VERSION 5.7 ;
  NOWIREEXTENSIONATPIN ON ;
  DIVIDERCHAR "/" ;
  BUSBITCHARS "[]" ;
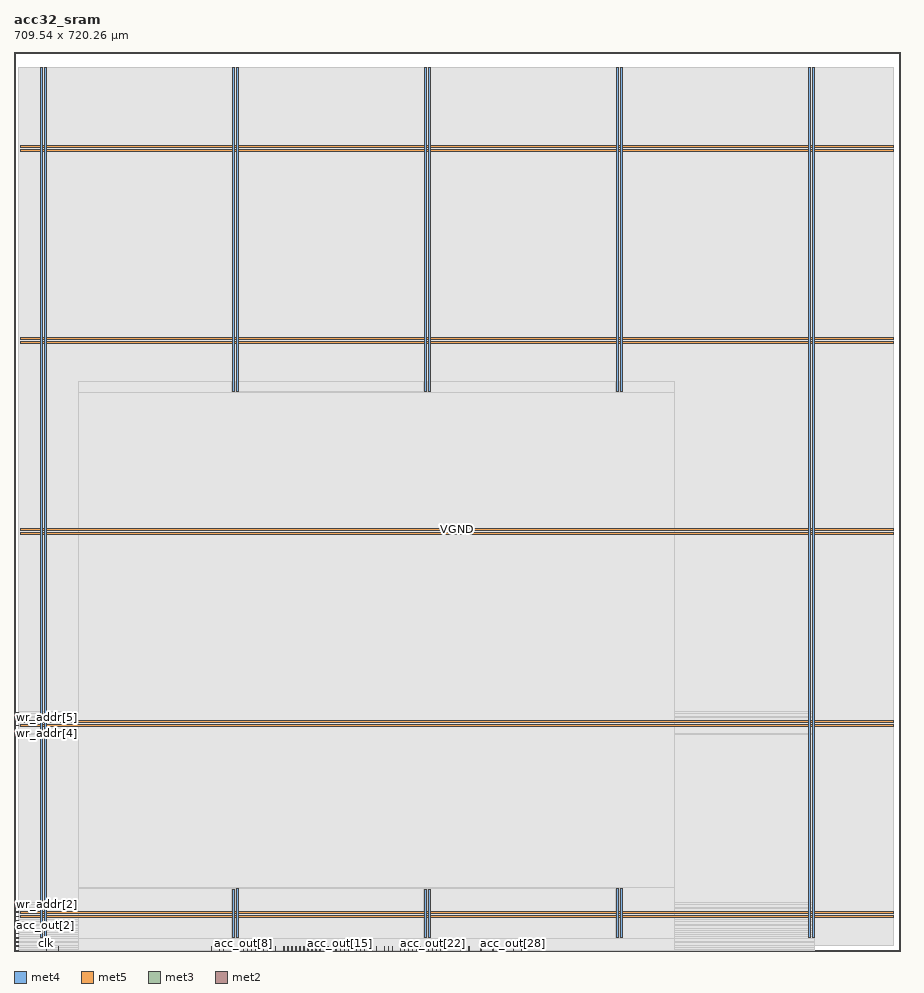
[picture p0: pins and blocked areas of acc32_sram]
MACRO acc32_sram
  CLASS BLOCK ;
  FOREIGN acc32_sram ;
  ORIGIN 0.000 0.000 ;
  SIZE 709.540 BY 720.260 ;
  PIN VGND
    DIRECTION INOUT ;
    USE GROUND ;
    PORT
      LAYER met4 ;
        RECT 24.340 10.640 25.940 707.440 ;
    END
    PORT
      LAYER met4 ;
        RECT 177.940 10.640 179.540 50.020 ;
    END
    PORT
      LAYER met4 ;
        RECT 177.940 447.480 179.540 707.440 ;
    END
    PORT
      LAYER met4 ;
        RECT 331.540 10.640 333.140 49.400 ;
    END
    PORT
      LAYER met4 ;
        RECT 331.540 447.480 333.140 707.440 ;
    END
    PORT
      LAYER met4 ;
        RECT 485.140 10.640 486.740 50.020 ;
    END
    PORT
      LAYER met4 ;
        RECT 485.140 447.480 486.740 707.440 ;
    END
    PORT
      LAYER met4 ;
        RECT 638.740 10.640 640.340 707.440 ;
    END
    PORT
      LAYER met5 ;
        RECT 5.280 30.030 704.040 31.630 ;
    END
    PORT
      LAYER met5 ;
        RECT 5.280 183.210 704.040 184.810 ;
    END
    PORT
      LAYER met5 ;
        RECT 5.280 336.390 704.040 337.990 ;
    END
    PORT
      LAYER met5 ;
        RECT 5.280 489.570 704.040 491.170 ;
    END
    PORT
      LAYER met5 ;
        RECT 5.280 642.750 704.040 644.350 ;
    END
  END VGND
  PIN VPWR
    DIRECTION INOUT ;
    USE POWER ;
    PORT
      LAYER met4 ;
        RECT 21.040 10.640 22.640 707.440 ;
    END
    PORT
      LAYER met4 ;
        RECT 174.640 10.640 176.240 49.400 ;
    END
    PORT
      LAYER met4 ;
        RECT 174.640 447.480 176.240 707.440 ;
    END
    PORT
      LAYER met4 ;
        RECT 328.240 10.640 329.840 49.400 ;
    END
    PORT
      LAYER met4 ;
        RECT 328.240 448.100 329.840 707.440 ;
    END
    PORT
      LAYER met4 ;
        RECT 481.840 10.640 483.440 50.020 ;
    END
    PORT
      LAYER met4 ;
        RECT 481.840 447.480 483.440 707.440 ;
    END
    PORT
      LAYER met4 ;
        RECT 635.440 10.640 637.040 707.440 ;
    END
    PORT
      LAYER met5 ;
        RECT 5.280 26.730 704.040 28.330 ;
    END
    PORT
      LAYER met5 ;
        RECT 5.280 179.910 704.040 181.510 ;
    END
    PORT
      LAYER met5 ;
        RECT 5.280 333.090 704.040 334.690 ;
    END
    PORT
      LAYER met5 ;
        RECT 5.280 486.270 704.040 487.870 ;
    END
    PORT
      LAYER met5 ;
        RECT 5.280 639.450 704.040 641.050 ;
    END
  END VPWR
  PIN acc_out[0]
    DIRECTION OUTPUT ;
    USE SIGNAL ;
    ANTENNADIFFAREA 0.445500 ;
    PORT
      LAYER met3 ;
        RECT 0.000 27.240 4.000 27.840 ;
    END
  END acc_out[0]
  PIN acc_out[10]
    DIRECTION OUTPUT ;
    USE SIGNAL ;
    ANTENNADIFFAREA 0.445500 ;
    PORT
      LAYER met2 ;
        RECT 206.170 0.000 206.450 4.000 ;
    END
  END acc_out[10]
  PIN acc_out[11]
    DIRECTION OUTPUT ;
    USE SIGNAL ;
    ANTENNADIFFAREA 0.445500 ;
    PORT
      LAYER met2 ;
        RECT 219.050 0.000 219.330 4.000 ;
    END
  END acc_out[11]
  PIN acc_out[12]
    DIRECTION OUTPUT ;
    USE SIGNAL ;
    ANTENNADIFFAREA 0.445500 ;
    PORT
      LAYER met2 ;
        RECT 225.490 0.000 225.770 4.000 ;
    END
  END acc_out[12]
  PIN acc_out[13]
    DIRECTION OUTPUT ;
    USE SIGNAL ;
    ANTENNADIFFAREA 0.445500 ;
    PORT
      LAYER met2 ;
        RECT 235.150 0.000 235.430 4.000 ;
    END
  END acc_out[13]
  PIN acc_out[14]
    DIRECTION OUTPUT ;
    USE SIGNAL ;
    ANTENNADIFFAREA 0.445500 ;
    PORT
      LAYER met2 ;
        RECT 241.590 0.000 241.870 4.000 ;
    END
  END acc_out[14]
  PIN acc_out[15]
    DIRECTION OUTPUT ;
    USE SIGNAL ;
    ANTENNADIFFAREA 0.445500 ;
    PORT
      LAYER met2 ;
        RECT 260.910 0.000 261.190 4.000 ;
    END
  END acc_out[15]
  PIN acc_out[16]
    DIRECTION OUTPUT ;
    USE SIGNAL ;
    ANTENNADIFFAREA 0.445500 ;
    PORT
      LAYER met2 ;
        RECT 270.570 0.000 270.850 4.000 ;
    END
  END acc_out[16]
  PIN acc_out[17]
    DIRECTION OUTPUT ;
    USE SIGNAL ;
    ANTENNADIFFAREA 0.445500 ;
    PORT
      LAYER met2 ;
        RECT 277.010 0.000 277.290 4.000 ;
    END
  END acc_out[17]
  PIN acc_out[18]
    DIRECTION OUTPUT ;
    USE SIGNAL ;
    ANTENNADIFFAREA 0.445500 ;
    PORT
      LAYER met2 ;
        RECT 283.450 0.000 283.730 4.000 ;
    END
  END acc_out[18]
  PIN acc_out[19]
    DIRECTION OUTPUT ;
    USE SIGNAL ;
    ANTENNADIFFAREA 0.445500 ;
    PORT
      LAYER met2 ;
        RECT 299.550 0.000 299.830 4.000 ;
    END
  END acc_out[19]
  PIN acc_out[1]
    DIRECTION OUTPUT ;
    USE SIGNAL ;
    ANTENNADIFFAREA 0.445500 ;
    PORT
      LAYER met3 ;
        RECT 0.000 17.040 4.000 17.640 ;
    END
  END acc_out[1]
  PIN acc_out[20]
    DIRECTION OUTPUT ;
    USE SIGNAL ;
    ANTENNADIFFAREA 0.445500 ;
    PORT
      LAYER met2 ;
        RECT 312.430 0.000 312.710 4.000 ;
    END
  END acc_out[20]
  PIN acc_out[21]
    DIRECTION OUTPUT ;
    USE SIGNAL ;
    ANTENNADIFFAREA 0.445500 ;
    PORT
      LAYER met2 ;
        RECT 322.090 0.000 322.370 4.000 ;
    END
  END acc_out[21]
  PIN acc_out[22]
    DIRECTION OUTPUT ;
    USE SIGNAL ;
    ANTENNADIFFAREA 0.445500 ;
    PORT
      LAYER met2 ;
        RECT 334.970 0.000 335.250 4.000 ;
    END
  END acc_out[22]
  PIN acc_out[23]
    DIRECTION OUTPUT ;
    USE SIGNAL ;
    ANTENNADIFFAREA 0.445500 ;
    PORT
      LAYER met2 ;
        RECT 341.410 0.000 341.690 4.000 ;
    END
  END acc_out[23]
  PIN acc_out[24]
    DIRECTION OUTPUT ;
    USE SIGNAL ;
    ANTENNADIFFAREA 0.445500 ;
    PORT
      LAYER met2 ;
        RECT 357.510 0.000 357.790 4.000 ;
    END
  END acc_out[24]
  PIN acc_out[25]
    DIRECTION OUTPUT ;
    USE SIGNAL ;
    ANTENNADIFFAREA 0.445500 ;
    PORT
      LAYER met2 ;
        RECT 363.950 0.000 364.230 4.000 ;
    END
  END acc_out[25]
  PIN acc_out[26]
    DIRECTION OUTPUT ;
    USE SIGNAL ;
    ANTENNADIFFAREA 0.445500 ;
    PORT
      LAYER met2 ;
        RECT 373.610 0.000 373.890 4.000 ;
    END
  END acc_out[26]
  PIN acc_out[27]
    DIRECTION OUTPUT ;
    USE SIGNAL ;
    ANTENNADIFFAREA 0.445500 ;
    PORT
      LAYER met2 ;
        RECT 383.270 0.000 383.550 4.000 ;
    END
  END acc_out[27]
  PIN acc_out[28]
    DIRECTION OUTPUT ;
    USE SIGNAL ;
    ANTENNADIFFAREA 0.445500 ;
    PORT
      LAYER met2 ;
        RECT 399.370 0.000 399.650 4.000 ;
    END
  END acc_out[28]
  PIN acc_out[29]
    DIRECTION OUTPUT ;
    USE SIGNAL ;
    ANTENNADIFFAREA 0.445500 ;
    PORT
      LAYER met2 ;
        RECT 405.810 0.000 406.090 4.000 ;
    END
  END acc_out[29]
  PIN acc_out[2]
    DIRECTION OUTPUT ;
    USE SIGNAL ;
    ANTENNADIFFAREA 0.445500 ;
    PORT
      LAYER met3 ;
        RECT 0.000 20.440 4.000 21.040 ;
    END
  END acc_out[2]
  PIN acc_out[30]
    DIRECTION OUTPUT ;
    USE SIGNAL ;
    ANTENNADIFFAREA 0.445500 ;
    PORT
      LAYER met2 ;
        RECT 409.030 0.000 409.310 4.000 ;
    END
  END acc_out[30]
  PIN acc_out[31]
    DIRECTION OUTPUT ;
    USE SIGNAL ;
    ANTENNADIFFAREA 0.445500 ;
    PORT
      LAYER met2 ;
        RECT 421.910 0.000 422.190 4.000 ;
    END
  END acc_out[31]
  PIN acc_out[3]
    DIRECTION OUTPUT ;
    USE SIGNAL ;
    ANTENNADIFFAREA 0.445500 ;
    PORT
      LAYER met3 ;
        RECT 0.000 10.240 4.000 10.840 ;
    END
  END acc_out[3]
  PIN acc_out[4]
    DIRECTION OUTPUT ;
    USE SIGNAL ;
    ANTENNADIFFAREA 0.445500 ;
    PORT
      LAYER met3 ;
        RECT 0.000 0.040 4.000 0.640 ;
    END
  END acc_out[4]
  PIN acc_out[5]
    DIRECTION OUTPUT ;
    USE SIGNAL ;
    ANTENNADIFFAREA 0.445500 ;
    PORT
      LAYER met3 ;
        RECT 0.000 13.640 4.000 14.240 ;
    END
  END acc_out[5]
  PIN acc_out[6]
    DIRECTION OUTPUT ;
    USE SIGNAL ;
    ANTENNADIFFAREA 0.445500 ;
    PORT
      LAYER met3 ;
        RECT 0.000 3.440 4.000 4.040 ;
    END
  END acc_out[6]
  PIN acc_out[7]
    DIRECTION OUTPUT ;
    USE SIGNAL ;
    ANTENNADIFFAREA 0.445500 ;
    PORT
      LAYER met3 ;
        RECT 0.000 6.840 4.000 7.440 ;
    END
  END acc_out[7]
  PIN acc_out[8]
    DIRECTION OUTPUT ;
    USE SIGNAL ;
    ANTENNADIFFAREA 0.445500 ;
    PORT
      LAYER met2 ;
        RECT 183.630 0.000 183.910 4.000 ;
    END
  END acc_out[8]
  PIN acc_out[9]
    DIRECTION OUTPUT ;
    USE SIGNAL ;
    ANTENNADIFFAREA 0.445500 ;
    PORT
      LAYER met2 ;
        RECT 193.290 0.000 193.570 4.000 ;
    END
  END acc_out[9]
  PIN clk
    DIRECTION INPUT ;
    USE SIGNAL ;
    ANTENNAGATEAREA 0.852000 ;
    PORT
      LAYER met2 ;
        RECT 25.850 0.000 26.130 4.000 ;
    END
  END clk
  PIN rst
    DIRECTION INPUT ;
    USE SIGNAL ;
    ANTENNAGATEAREA 0.196500 ;
    PORT
      LAYER met2 ;
        RECT 35.510 0.000 35.790 4.000 ;
    END
  END rst
  PIN wr_addr[0]
    DIRECTION INPUT ;
    USE SIGNAL ;
    ANTENNAGATEAREA 0.196500 ;
    PORT
      LAYER met3 ;
        RECT 0.000 34.040 4.000 34.640 ;
    END
  END wr_addr[0]
  PIN wr_addr[1]
    DIRECTION INPUT ;
    USE SIGNAL ;
    ANTENNAGATEAREA 0.196500 ;
    PORT
      LAYER met3 ;
        RECT 0.000 23.840 4.000 24.440 ;
    END
  END wr_addr[1]
  PIN wr_addr[2]
    DIRECTION INPUT ;
    USE SIGNAL ;
    ANTENNAGATEAREA 0.196500 ;
    PORT
      LAYER met3 ;
        RECT 0.000 30.640 4.000 31.240 ;
    END
  END wr_addr[2]
  PIN wr_addr[3]
    DIRECTION INPUT ;
    USE SIGNAL ;
    ANTENNAGATEAREA 0.196500 ;
    PORT
      LAYER met3 ;
        RECT 0.000 37.440 4.000 38.040 ;
    END
  END wr_addr[3]
  PIN wr_addr[4]
    DIRECTION INPUT ;
    USE SIGNAL ;
    ANTENNAGATEAREA 0.196500 ;
    PORT
      LAYER met3 ;
        RECT 0.000 173.440 4.000 174.040 ;
    END
  END wr_addr[4]
  PIN wr_addr[5]
    DIRECTION INPUT ;
    USE SIGNAL ;
    ANTENNAGATEAREA 0.196500 ;
    PORT
      LAYER met3 ;
        RECT 0.000 180.240 4.000 180.840 ;
    END
  END wr_addr[5]
  PIN wr_addr[6]
    DIRECTION INPUT ;
    USE SIGNAL ;
    ANTENNAGATEAREA 0.196500 ;
    PORT
      LAYER met3 ;
        RECT 0.000 183.640 4.000 184.240 ;
    END
  END wr_addr[6]
  PIN wr_addr[7]
    DIRECTION INPUT ;
    USE SIGNAL ;
    ANTENNAGATEAREA 0.196500 ;
    PORT
      LAYER met3 ;
        RECT 0.000 190.440 4.000 191.040 ;
    END
  END wr_addr[7]
  PIN wr_data[0]
    DIRECTION INPUT ;
    USE SIGNAL ;
    ANTENNAGATEAREA 0.196500 ;
    PORT
      LAYER met2 ;
        RECT 157.870 0.000 158.150 4.000 ;
    END
  END wr_data[0]
  PIN wr_data[10]
    DIRECTION INPUT ;
    USE SIGNAL ;
    ANTENNAGATEAREA 0.196500 ;
    PORT
      LAYER met2 ;
        RECT 215.830 0.000 216.110 4.000 ;
    END
  END wr_data[10]
  PIN wr_data[11]
    DIRECTION INPUT ;
    USE SIGNAL ;
    ANTENNAGATEAREA 0.196500 ;
    PORT
      LAYER met2 ;
        RECT 222.270 0.000 222.550 4.000 ;
    END
  END wr_data[11]
  PIN wr_data[12]
    DIRECTION INPUT ;
    USE SIGNAL ;
    ANTENNAGATEAREA 0.196500 ;
    PORT
      LAYER met2 ;
        RECT 228.710 0.000 228.990 4.000 ;
    END
  END wr_data[12]
  PIN wr_data[13]
    DIRECTION INPUT ;
    USE SIGNAL ;
    ANTENNAGATEAREA 0.196500 ;
    PORT
      LAYER met2 ;
        RECT 231.930 0.000 232.210 4.000 ;
    END
  END wr_data[13]
  PIN wr_data[14]
    DIRECTION INPUT ;
    USE SIGNAL ;
    ANTENNAGATEAREA 0.196500 ;
    PORT
      LAYER met2 ;
        RECT 238.370 0.000 238.650 4.000 ;
    END
  END wr_data[14]
  PIN wr_data[15]
    DIRECTION INPUT ;
    USE SIGNAL ;
    ANTENNAGATEAREA 0.196500 ;
    PORT
      LAYER met2 ;
        RECT 244.810 0.000 245.090 4.000 ;
    END
  END wr_data[15]
  PIN wr_data[16]
    DIRECTION INPUT ;
    USE SIGNAL ;
    ANTENNAGATEAREA 0.196500 ;
    PORT
      LAYER met2 ;
        RECT 251.250 0.000 251.530 4.000 ;
    END
  END wr_data[16]
  PIN wr_data[17]
    DIRECTION INPUT ;
    USE SIGNAL ;
    ANTENNAGATEAREA 0.196500 ;
    PORT
      LAYER met2 ;
        RECT 257.690 0.000 257.970 4.000 ;
    END
  END wr_data[17]
  PIN wr_data[18]
    DIRECTION INPUT ;
    USE SIGNAL ;
    ANTENNAGATEAREA 0.196500 ;
    PORT
      LAYER met2 ;
        RECT 264.130 0.000 264.410 4.000 ;
    END
  END wr_data[18]
  PIN wr_data[19]
    DIRECTION INPUT ;
    USE SIGNAL ;
    ANTENNAGATEAREA 0.196500 ;
    PORT
      LAYER met2 ;
        RECT 267.350 0.000 267.630 4.000 ;
    END
  END wr_data[19]
  PIN wr_data[1]
    DIRECTION INPUT ;
    USE SIGNAL ;
    ANTENNAGATEAREA 0.196500 ;
    PORT
      LAYER met2 ;
        RECT 164.310 0.000 164.590 4.000 ;
    END
  END wr_data[1]
  PIN wr_data[20]
    DIRECTION INPUT ;
    USE SIGNAL ;
    ANTENNAGATEAREA 0.196500 ;
    PORT
      LAYER met2 ;
        RECT 273.790 0.000 274.070 4.000 ;
    END
  END wr_data[20]
  PIN wr_data[21]
    DIRECTION INPUT ;
    USE SIGNAL ;
    ANTENNAGATEAREA 0.196500 ;
    PORT
      LAYER met2 ;
        RECT 280.230 0.000 280.510 4.000 ;
    END
  END wr_data[21]
  PIN wr_data[22]
    DIRECTION INPUT ;
    USE SIGNAL ;
    ANTENNAGATEAREA 0.196500 ;
    PORT
      LAYER met2 ;
        RECT 286.670 0.000 286.950 4.000 ;
    END
  END wr_data[22]
  PIN wr_data[23]
    DIRECTION INPUT ;
    USE SIGNAL ;
    ANTENNAGATEAREA 0.196500 ;
    PORT
      LAYER met2 ;
        RECT 289.890 0.000 290.170 4.000 ;
    END
  END wr_data[23]
  PIN wr_data[24]
    DIRECTION INPUT ;
    USE SIGNAL ;
    ANTENNAGATEAREA 0.196500 ;
    PORT
      LAYER met2 ;
        RECT 296.330 0.000 296.610 4.000 ;
    END
  END wr_data[24]
  PIN wr_data[25]
    DIRECTION INPUT ;
    USE SIGNAL ;
    ANTENNAGATEAREA 0.196500 ;
    PORT
      LAYER met2 ;
        RECT 302.770 0.000 303.050 4.000 ;
    END
  END wr_data[25]
  PIN wr_data[26]
    DIRECTION INPUT ;
    USE SIGNAL ;
    ANTENNAGATEAREA 0.196500 ;
    PORT
      LAYER met2 ;
        RECT 309.210 0.000 309.490 4.000 ;
    END
  END wr_data[26]
  PIN wr_data[27]
    DIRECTION INPUT ;
    USE SIGNAL ;
    ANTENNAGATEAREA 0.196500 ;
    PORT
      LAYER met2 ;
        RECT 315.650 0.000 315.930 4.000 ;
    END
  END wr_data[27]
  PIN wr_data[28]
    DIRECTION INPUT ;
    USE SIGNAL ;
    ANTENNAGATEAREA 0.196500 ;
    PORT
      LAYER met2 ;
        RECT 318.870 0.000 319.150 4.000 ;
    END
  END wr_data[28]
  PIN wr_data[29]
    DIRECTION INPUT ;
    USE SIGNAL ;
    ANTENNAGATEAREA 0.196500 ;
    PORT
      LAYER met2 ;
        RECT 325.310 0.000 325.590 4.000 ;
    END
  END wr_data[29]
  PIN wr_data[2]
    DIRECTION INPUT ;
    USE SIGNAL ;
    ANTENNAGATEAREA 0.196500 ;
    PORT
      LAYER met2 ;
        RECT 167.530 0.000 167.810 4.000 ;
    END
  END wr_data[2]
  PIN wr_data[30]
    DIRECTION INPUT ;
    USE SIGNAL ;
    ANTENNAGATEAREA 0.196500 ;
    PORT
      LAYER met2 ;
        RECT 331.750 0.000 332.030 4.000 ;
    END
  END wr_data[30]
  PIN wr_data[31]
    DIRECTION INPUT ;
    USE SIGNAL ;
    ANTENNAGATEAREA 0.196500 ;
    PORT
      LAYER met2 ;
        RECT 338.190 0.000 338.470 4.000 ;
    END
  END wr_data[31]
  PIN wr_data[3]
    DIRECTION INPUT ;
    USE SIGNAL ;
    ANTENNAGATEAREA 0.196500 ;
    PORT
      LAYER met2 ;
        RECT 173.970 0.000 174.250 4.000 ;
    END
  END wr_data[3]
  PIN wr_data[4]
    DIRECTION INPUT ;
    USE SIGNAL ;
    ANTENNAGATEAREA 0.196500 ;
    PORT
      LAYER met2 ;
        RECT 180.410 0.000 180.690 4.000 ;
    END
  END wr_data[4]
  PIN wr_data[5]
    DIRECTION INPUT ;
    USE SIGNAL ;
    ANTENNAGATEAREA 0.196500 ;
    PORT
      LAYER met2 ;
        RECT 186.850 0.000 187.130 4.000 ;
    END
  END wr_data[5]
  PIN wr_data[6]
    DIRECTION INPUT ;
    USE SIGNAL ;
    ANTENNAGATEAREA 0.196500 ;
    PORT
      LAYER met2 ;
        RECT 190.070 0.000 190.350 4.000 ;
    END
  END wr_data[6]
  PIN wr_data[7]
    DIRECTION INPUT ;
    USE SIGNAL ;
    ANTENNAGATEAREA 0.196500 ;
    PORT
      LAYER met2 ;
        RECT 199.730 0.000 200.010 4.000 ;
    END
  END wr_data[7]
  PIN wr_data[8]
    DIRECTION INPUT ;
    USE SIGNAL ;
    ANTENNAGATEAREA 0.196500 ;
    PORT
      LAYER met2 ;
        RECT 202.950 0.000 203.230 4.000 ;
    END
  END wr_data[8]
  PIN wr_data[9]
    DIRECTION INPUT ;
    USE SIGNAL ;
    ANTENNAGATEAREA 0.196500 ;
    PORT
      LAYER met2 ;
        RECT 209.390 0.000 209.670 4.000 ;
    END
  END wr_data[9]
  PIN wr_en
    DIRECTION INPUT ;
    USE SIGNAL ;
    ANTENNAGATEAREA 0.213000 ;
    PORT
      LAYER met3 ;
        RECT 0.000 187.040 4.000 187.640 ;
    END
  END wr_en
  OBS
      LAYER nwell ;
        RECT 5.330 10.795 703.990 707.285 ;
      LAYER li1 ;
        RECT 5.520 10.795 703.800 707.285 ;
      LAYER met1 ;
        RECT 4.210 4.800 703.800 707.440 ;
      LAYER met2 ;
        RECT 4.230 4.280 640.310 707.385 ;
        RECT 4.230 0.155 25.570 4.280 ;
        RECT 26.410 0.155 35.230 4.280 ;
        RECT 36.070 0.155 157.590 4.280 ;
        RECT 158.430 0.155 164.030 4.280 ;
        RECT 164.870 0.155 167.250 4.280 ;
        RECT 168.090 0.155 173.690 4.280 ;
        RECT 174.530 0.155 180.130 4.280 ;
        RECT 180.970 0.155 183.350 4.280 ;
        RECT 184.190 0.155 186.570 4.280 ;
        RECT 187.410 0.155 189.790 4.280 ;
        RECT 190.630 0.155 193.010 4.280 ;
        RECT 193.850 0.155 199.450 4.280 ;
        RECT 200.290 0.155 202.670 4.280 ;
        RECT 203.510 0.155 205.890 4.280 ;
        RECT 206.730 0.155 209.110 4.280 ;
        RECT 209.950 0.155 215.550 4.280 ;
        RECT 216.390 0.155 218.770 4.280 ;
        RECT 219.610 0.155 221.990 4.280 ;
        RECT 222.830 0.155 225.210 4.280 ;
        RECT 226.050 0.155 228.430 4.280 ;
        RECT 229.270 0.155 231.650 4.280 ;
        RECT 232.490 0.155 234.870 4.280 ;
        RECT 235.710 0.155 238.090 4.280 ;
        RECT 238.930 0.155 241.310 4.280 ;
        RECT 242.150 0.155 244.530 4.280 ;
        RECT 245.370 0.155 250.970 4.280 ;
        RECT 251.810 0.155 257.410 4.280 ;
        RECT 258.250 0.155 260.630 4.280 ;
        RECT 261.470 0.155 263.850 4.280 ;
        RECT 264.690 0.155 267.070 4.280 ;
        RECT 267.910 0.155 270.290 4.280 ;
        RECT 271.130 0.155 273.510 4.280 ;
        RECT 274.350 0.155 276.730 4.280 ;
        RECT 277.570 0.155 279.950 4.280 ;
        RECT 280.790 0.155 283.170 4.280 ;
        RECT 284.010 0.155 286.390 4.280 ;
        RECT 287.230 0.155 289.610 4.280 ;
        RECT 290.450 0.155 296.050 4.280 ;
        RECT 296.890 0.155 299.270 4.280 ;
        RECT 300.110 0.155 302.490 4.280 ;
        RECT 303.330 0.155 308.930 4.280 ;
        RECT 309.770 0.155 312.150 4.280 ;
        RECT 312.990 0.155 315.370 4.280 ;
        RECT 316.210 0.155 318.590 4.280 ;
        RECT 319.430 0.155 321.810 4.280 ;
        RECT 322.650 0.155 325.030 4.280 ;
        RECT 325.870 0.155 331.470 4.280 ;
        RECT 332.310 0.155 334.690 4.280 ;
        RECT 335.530 0.155 337.910 4.280 ;
        RECT 338.750 0.155 341.130 4.280 ;
        RECT 341.970 0.155 357.230 4.280 ;
        RECT 358.070 0.155 363.670 4.280 ;
        RECT 364.510 0.155 373.330 4.280 ;
        RECT 374.170 0.155 382.990 4.280 ;
        RECT 383.830 0.155 399.090 4.280 ;
        RECT 399.930 0.155 405.530 4.280 ;
        RECT 406.370 0.155 408.750 4.280 ;
        RECT 409.590 0.155 421.630 4.280 ;
        RECT 422.470 0.155 640.310 4.280 ;
      LAYER met3 ;
        RECT 3.990 191.440 640.330 707.365 ;
        RECT 4.400 190.040 640.330 191.440 ;
        RECT 3.990 188.040 640.330 190.040 ;
        RECT 4.400 186.640 640.330 188.040 ;
        RECT 3.990 184.640 640.330 186.640 ;
        RECT 4.400 183.240 640.330 184.640 ;
        RECT 3.990 181.240 640.330 183.240 ;
        RECT 4.400 179.840 640.330 181.240 ;
        RECT 3.990 174.440 640.330 179.840 ;
        RECT 4.400 173.040 640.330 174.440 ;
        RECT 3.990 38.440 640.330 173.040 ;
        RECT 4.400 37.040 640.330 38.440 ;
        RECT 3.990 35.040 640.330 37.040 ;
        RECT 4.400 33.640 640.330 35.040 ;
        RECT 3.990 31.640 640.330 33.640 ;
        RECT 4.400 30.240 640.330 31.640 ;
        RECT 3.990 28.240 640.330 30.240 ;
        RECT 4.400 26.840 640.330 28.240 ;
        RECT 3.990 24.840 640.330 26.840 ;
        RECT 4.400 23.440 640.330 24.840 ;
        RECT 3.990 21.440 640.330 23.440 ;
        RECT 4.400 20.040 640.330 21.440 ;
        RECT 3.990 18.040 640.330 20.040 ;
        RECT 4.400 16.640 640.330 18.040 ;
        RECT 3.990 14.640 640.330 16.640 ;
        RECT 4.400 13.240 640.330 14.640 ;
        RECT 3.990 11.240 640.330 13.240 ;
        RECT 4.400 9.840 640.330 11.240 ;
        RECT 3.990 7.840 640.330 9.840 ;
        RECT 4.400 6.440 640.330 7.840 ;
        RECT 3.990 4.440 640.330 6.440 ;
        RECT 4.400 3.040 640.330 4.440 ;
        RECT 3.990 1.040 640.330 3.040 ;
        RECT 4.400 0.175 640.330 1.040 ;
      LAYER met4 ;
        RECT 51.360 447.080 174.240 456.105 ;
        RECT 176.640 447.080 177.540 456.105 ;
        RECT 179.940 447.700 327.840 456.105 ;
        RECT 330.240 447.700 331.140 456.105 ;
        RECT 179.940 447.080 331.140 447.700 ;
        RECT 333.540 447.080 481.440 456.105 ;
        RECT 483.840 447.080 484.740 456.105 ;
        RECT 487.140 447.080 528.420 456.105 ;
        RECT 51.360 50.420 528.420 447.080 ;
        RECT 51.360 49.800 177.540 50.420 ;
        RECT 51.360 10.240 174.240 49.800 ;
        RECT 176.640 10.240 177.540 49.800 ;
        RECT 179.940 49.800 481.440 50.420 ;
        RECT 179.940 10.240 327.840 49.800 ;
        RECT 330.240 10.240 331.140 49.800 ;
        RECT 333.540 10.240 481.440 49.800 ;
        RECT 483.840 10.240 484.740 50.420 ;
        RECT 487.140 10.240 528.420 50.420 ;
        RECT 51.360 0.175 528.420 10.240 ;
  END
END acc32_sram
END LIBRARY

